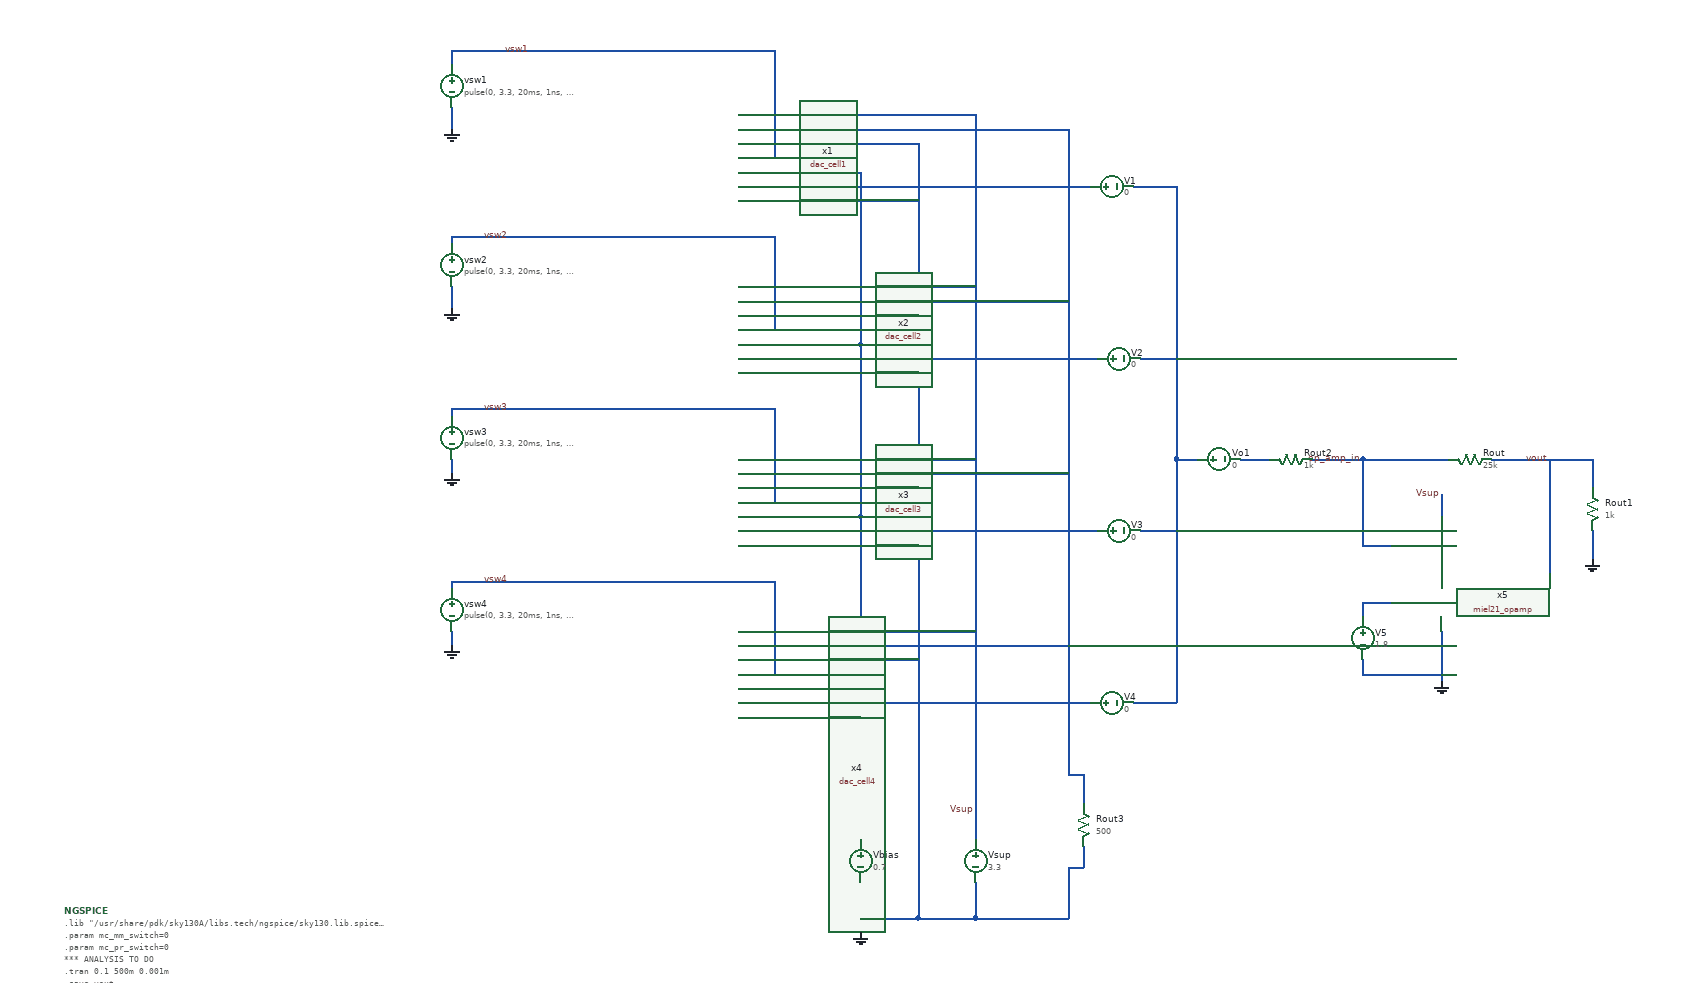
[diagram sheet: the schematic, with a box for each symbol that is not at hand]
v {xschem version=2.9.9 file_version=1.2 }
G {}
K {}
V {}
S {}
E {}
N 1600 -1150 1600 -940 { lab=#net1}
N 1430 -1150 1600 -1150 { lab=#net1}
N 1430 -1390 1600 -1390 { lab=#net1}
N 1600 -1390 1600 -1150 { lab=#net1}
N 1600 -1630 1600 -1390 { lab=#net1}
N 1430 -1630 1600 -1630 { lab=#net1}
N 1600 -1860 1600 -1630 { lab=#net1}
N 1600 -1870 1600 -1860 { lab=#net1}
N 1430 -1870 1600 -1870 { lab=#net1}
N 1600 -870 1600 -810 { lab=GND}
N 1600 -830 1680 -830 { lab=GND}
N 1680 -1890 1680 -830 { lab=GND}
N 1430 -1910 1680 -1910 { lab=GND}
N 1680 -1910 1680 -1890 { lab=GND}
N 1430 -1670 1680 -1670 { lab=GND}
N 1430 -1430 1680 -1430 { lab=GND}
N 1430 -1190 1680 -1190 { lab=GND}
N 1600 -880 1600 -870 { lab=GND}
N 1760 -880 1760 -830 { lab=GND}
N 1680 -830 1760 -830 { lab=GND}
N 1760 -1950 1760 -940 { lab=Vsup}
N 1430 -1950 1760 -1950 { lab=Vsup}
N 1430 -1710 1760 -1710 { lab=Vsup}
N 1430 -1470 1760 -1470 { lab=Vsup}
N 1430 -1230 1760 -1230 { lab=Vsup}
N 1890 -880 1890 -830 { lab=GND}
N 1760 -830 1890 -830 { lab=GND}
N 1430 -1930 1890 -1930 { lab=#net2}
N 1430 -1690 1890 -1690 { lab=#net2}
N 1430 -1450 1890 -1450 { lab=#net2}
N 1430 -1210 1890 -1210 { lab=#net2}
N 2480 -1470 2620 -1470 { lab=vout}
N 1480 -2000 1480 -1890 { lab=vsw1}
N 1430 -1890 1480 -1890 { lab=vsw1}
N 1480 -1760 1480 -1650 { lab=vsw2}
N 1430 -1650 1480 -1650 { lab=vsw2}
N 1480 -1520 1480 -1410 { lab=vsw3}
N 1430 -1410 1480 -1410 { lab=vsw3}
N 1480 -1280 1480 -1170 { lab=vsw4}
N 1430 -1170 1480 -1170 { lab=vsw4}
N 1480 -2040 1480 -2000 { lab=vsw1}
N 1030 -2040 1480 -2040 { lab=vsw1}
N 1030 -2040 1030 -2020 { lab=vsw1}
N 1030 -1780 1030 -1770 { lab=vsw2}
N 1030 -1780 1480 -1780 { lab=vsw2}
N 1480 -1780 1480 -1760 { lab=vsw2}
N 1030 -1540 1030 -1530 { lab=vsw3}
N 1030 -1540 1480 -1540 { lab=vsw3}
N 1480 -1540 1480 -1520 { lab=vsw3}
N 1030 -1300 1030 -1290 { lab=vsw4}
N 1030 -1300 1480 -1300 { lab=vsw4}
N 1480 -1300 1480 -1280 { lab=vsw4}
N 1030 -1470 1030 -1450 { lab=GND}
N 1030 -1230 1030 -1210 { lab=GND}
N 1030 -1710 1030 -1680 { lab=GND}
N 1030 -1960 1030 -1930 { lab=GND}
N 2040 -1820 2040 -1470 { lab=#net3}
N 2040 -1470 2040 -1350 { lab=#net3}
N 2040 -1850 2040 -1820 { lab=#net3}
N 2410 -1420 2410 -1390 { lab=Vsup}
N 2410 -1230 2410 -1210 { lab=GND}
N 2410 -1210 2410 -1160 { lab=GND}
N 2300 -1190 2300 -1170 { lab=GND}
N 2300 -1170 2410 -1170 { lab=GND}
N 2040 -1350 2040 -1130 { lab=#net3}
N 2300 -1470 2340 -1470 { lab=op_amp_in}
N 2400 -1470 2420 -1470 { lab=op_amp_in}
N 1980 -1850 2040 -1850 { lab=#net3}
N 1990 -1610 2040 -1610 { lab=#net3}
N 1990 -1370 2040 -1370 { lab=#net3}
N 1980 -1130 2040 -1130 { lab=#net3}
N 2040 -1470 2060 -1470 { lab=#net3}
N 2340 -1470 2400 -1470 { lab=op_amp_in}
N 2620 -1470 2620 -1430 { lab=vout}
N 2620 -1370 2620 -1330 { lab=GND}
N 1900 -1610 1930 -1610 { lab=#net4}
N 2560 -1470 2560 -1310 { lab=vout}
N 2300 -1350 2340 -1350 { lab=op_amp_in}
N 2300 -1270 2340 -1270 { lab=#net5}
N 2300 -1270 2300 -1250 { lab=#net5}
N 1900 -1370 1930 -1370 { lab=#net6}
N 1900 -1130 1920 -1130 { lab=#net7}
N 1910 -1850 1920 -1850 { lab=#net8}
N 2300 -1470 2300 -1350 { lab=op_amp_in}
N 2060 -1470 2070 -1470 { lab=#net3}
N 1900 -1850 1910 -1850 { lab=#net8}
N 2130 -1470 2170 -1470 { lab=#net9}
N 2230 -1470 2300 -1470 { lab=op_amp_in}
N 1910 -1030 1910 -990 { lab=#net2}
N 1890 -1030 1910 -1030 { lab=#net2}
N 1910 -930 1910 -900 { lab=GND}
N 1890 -900 1910 -900 { lab=GND}
N 1890 -900 1890 -880 { lab=GND}
N 1890 -1930 1890 -1030 { lab=#net2}
N 1850 -1130 1900 -1130 {}
N 1840 -1370 1900 -1370 {}
N 1830 -1610 1900 -1610 {}
N 1830 -1850 1900 -1850 {}
N 1430 -1850 1830 -1850 {}
N 1430 -1610 1830 -1610 {}
N 1430 -1830 1680 -1830 {}
N 1430 -1590 1680 -1590 {}
N 1430 -1350 1680 -1350 {}
N 1430 -1370 1840 -1370 {}
N 1430 -1130 1850 -1130 {}
N 1430 -1110 1600 -1110 {}
C {/opt/uniccass/dev/dac_cell1/tb/dac_cell1.sym} 1280 -1890 0 0 {name=x1}
C {/opt/uniccass/dev/dac_cell2/tb/dac_cell2.sym} 1280 -1650 0 0 {name=x2}
C {/opt/uniccass/dev/dac_cell3/tb/dac_cell3.sym} 1280 -1410 0 0 {name=x3}
C {/opt/uniccass/dev/dac_cell4/tb/dac_cell4.sym} 1280 -1170 0 0 {name=x4}
C {devices/vsource.sym} 1030 -1990 0 0 {name=vsw1 value="pulse(0, 3.3, 20ms, 1ns, 1ns, 10ms, 20ms)"
}
C {devices/vsource.sym} 1030 -1740 0 0 {name=vsw2 value="pulse(0, 3.3, 20ms, 1ns, 1ns, 20ms, 40ms)"}
C {devices/vsource.sym} 1030 -1500 0 0 {name=vsw3 value="pulse(0, 3.3, 20ms, 1ns, 1ns, 40ms, 80ms)"}
C {devices/vsource.sym} 1030 -1260 0 0 {name=vsw4 value="pulse(0, 3.3, 20ms, 1ns, 1ns, 80ms, 160ms)"}
C {devices/gnd.sym} 1030 -1210 0 0 {name=l4 lab=GND}
C {devices/gnd.sym} 1030 -1450 0 0 {name=l5 lab=GND}
C {devices/gnd.sym} 1030 -1680 0 0 {name=l6 lab=GND}
C {devices/gnd.sym} 1030 -1930 0 0 {name=l7 lab=GND}
C {devices/gnd.sym} 1600 -810 0 0 {name=l1 lab=GND}
C {devices/vsource.sym} 1760 -910 0 0 {name=Vsup value=3.3}
C {devices/vsource.sym} 1600 -910 0 0 {name=Vbias value=0.7}
C {devices/res.sym} 2450 -1470 1 0 {name=Rout
value=25k
footprint=1206
device=resistor
m=1}
C {devices/lab_wire.sym} 2300 -1470 1 0 {name=l2 sig_type=std_logic lab=op_amp_in}
C {devices/lab_wire.sym} 1760 -980 0 0 {name=l3 sig_type=std_logic lab=Vsup}
C {devices/code_shown.sym} 490 -840 0 0 {name=NGSPICE
only_toplevel=true
value="
.lib \\"/usr/share/pdk/sky130A/libs.tech/ngspice/sky130.lib.spice\\" tt
.param mc_mm_switch=0
.param mc_pr_switch=0
*** ANALYSIS TO DO

.tran 0.1 500m 0.001m
.save vout
.save i(Vo1)
.save i(V1)
.save i(V2)
.save i(V3)
.save i(V4)
.save op_amp_in
.save output
.save vsw1 vsw2 vsw3 vsw4

.control
set wr_vecnames
set wr_singlescale

run
******** results filename  ************ nodes to write
wrdata $DEV_PATH/res/dac_top_cell_with_opamp_vout_tran_vol.res vout
wrdata $DEV_PATH/res/dac_top_cell_with_opamp_vsw1_tran_vol.res vsw1
wrdata $DEV_PATH/res/dac_top_cell_with_opamp_vsw2_tran_vol.res vsw2
wrdata $DEV_PATH/res/dac_top_cell_with_opamp_vsw3_tran_vol.res vsw3
wrdata $DEV_PATH/res/dac_top_cell_with_opamp_vsw4_tran_vol.res vsw4
.endc
"}
C {devices/lab_wire.sym} 1140 -2040 1 0 {name=l8 sig_type=std_logic lab=vsw1}
C {devices/lab_wire.sym} 1110 -1780 1 0 {name=l9 sig_type=std_logic lab=vsw2}
C {devices/lab_wire.sym} 1110 -1540 1 0 {name=l10 sig_type=std_logic lab=vsw3}
C {devices/lab_wire.sym} 1110 -1300 1 0 {name=l11 sig_type=std_logic lab=vsw4}
C {devices/gnd.sym} 2620 -1330 0 0 {name=l12 lab=GND}
C {devices/lab_wire.sym} 2560 -1470 1 0 {name=l13 sig_type=std_logic lab=vout}
C {/opt/uniccass/dev/opamp/miel21_opamp.sym} 2490 -1310 0 0 {name=x5}
C {devices/lab_wire.sym} 2410 -1420 0 0 {name=l14 sig_type=std_logic lab=Vsup}
C {devices/gnd.sym} 2410 -1160 0 0 {name=l15 lab=GND}
C {devices/vsource.sym} 1950 -1850 3 0 {name=V1 value=0}
C {devices/vsource.sym} 1960 -1610 3 0 {name=V2 value=0}
C {devices/vsource.sym} 1960 -1370 3 0 {name=V3 value=0}
C {devices/vsource.sym} 1950 -1130 3 0 {name=V4 value=0}
C {devices/vsource.sym} 2100 -1470 3 0 {name=Vo1 value=0}
C {devices/res.sym} 2620 -1400 0 0 {name=Rout1
value=1k
footprint=1206
device=resistor
m=1}
C {devices/vsource.sym} 2300 -1220 0 0 {name=V5 value=1.8}
C {devices/res.sym} 2200 -1470 1 0 {name=Rout2
value=1k
footprint=1206
device=resistor
m=1}
C {devices/res.sym} 1910 -960 0 0 {name=Rout3
value=500
footprint=1206
device=resistor
m=1}
